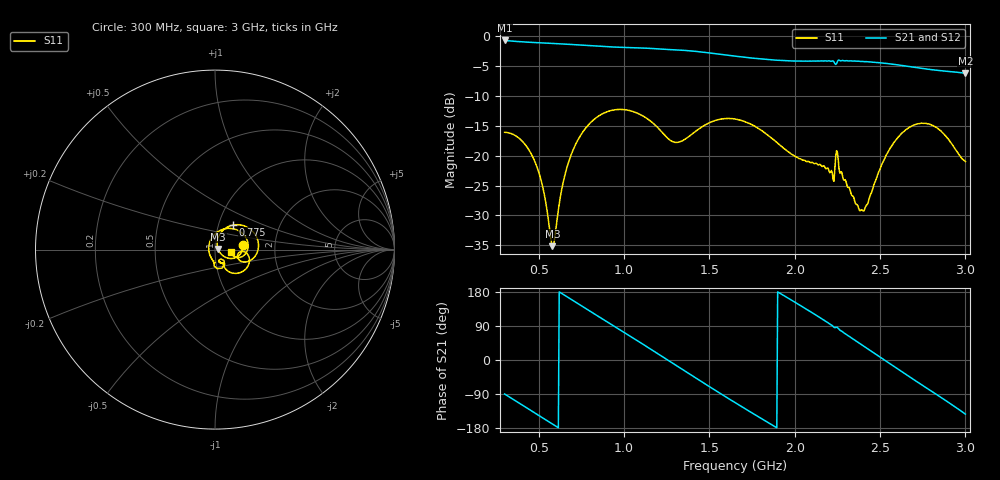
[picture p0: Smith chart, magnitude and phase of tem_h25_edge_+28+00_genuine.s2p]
! tem_h25_edge_+28+00_genuine
! simulated by sim/fixtures_fdtd.py (S12 = S21, S22 not computed)
# HZ S RI R 50
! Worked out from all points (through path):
!   541 points, 300 MHz to 3 GHz, reference 50 ohm
!   highest |S21| = -0.69 dB at 300 MHz (marker M1); lowest = -6.2 dB at 3 GHz (marker M2)
!   group delay of S21, straight-line fit = 789 ps
!   lowest |S11| = -35.1 dB at 580 MHz (marker M3), VSWR 1.04, Z = 51.7 + j0.4 ohm
!   |S11| at or under -10 dB: start of sweep to end of sweep
!   |S22| runs from - to - dB; largest |S21 - S12| = 0
!   S11 on the Smith chart (normalised r, x): 300 MHz: 1.37, +0.07; 775 MHz: 1.18, +0.33; 3 GHz: 1.19, -0.03
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3e8  0.1552 0.0254  0.00404 -0.9232  0.00404 -0.9232  0 0
4.75e8  0.0769 -0.0487  -0.6705 -0.5805  -0.6705 -0.5805  0 0
5.25e8  0.0423 -0.0326  -0.7854 -0.3961  -0.7854 -0.3961  0 0
5.8e8  0.0171 0.00387  -0.8554 -0.169  -0.8554 -0.169  0 0
6.6e8  0.0198 0.0724  -0.8422 0.1722  -0.8422 0.1722  0 0
7.5e8  0.0787 0.1299  -0.6734 0.5084  -0.6734 0.5084  0 0
7.75e8  0.1016 0.1367  -0.6026 0.584  -0.6026 0.584  0 0
8.8e8  0.1964 0.114  -0.2332 0.7874  -0.2332 0.7874  0 0
9.8e8  0.2412 0.0385  0.1601 0.793  0.1601 0.793  0 0
1.08e9  0.2236 -0.0365  0.5107 0.6165  0.5107 0.6165  0 0
1.2e9  0.1561 -0.0685  0.7543 0.2155  0.7543 0.2155  0 0
1.32e9  0.1276 -0.0245  0.7292 -0.2407  0.7292 -0.2407  0 0
1.45e9  0.1712 -0.0164  0.414 -0.6131  0.414 -0.6131  0 0
1.65e9  0.1725 -0.1074  -0.2592 -0.6316  -0.2592 -0.6316  0 0
1.87e9  0.0708 -0.1188  -0.6285 -0.0866  -0.6285 -0.0866  0 0
2.1e9  0.044 -0.0762  -0.359 0.5054  -0.359 0.5054  0 0
2.22e9  0.0218 -0.0686  -0.00797 0.6218  -0.00797 0.6218  0 0
2.25e9  0.0125 -0.1062  0.0449 0.6118  0.0449 0.6118  0 0
2.395e9  -0.0352 -0.00214  0.4763 0.392  0.4763 0.392  0 0
2.55e9  0.0273 0.106  0.5842 -0.0769  0.5842 -0.0769  0 0
2.775e9  0.1844 0.0195  0.141 -0.5125  0.141 -0.5125  0 0
3e9  0.0888 -0.011  -0.3905 -0.2971  -0.3905 -0.2971  0 0
